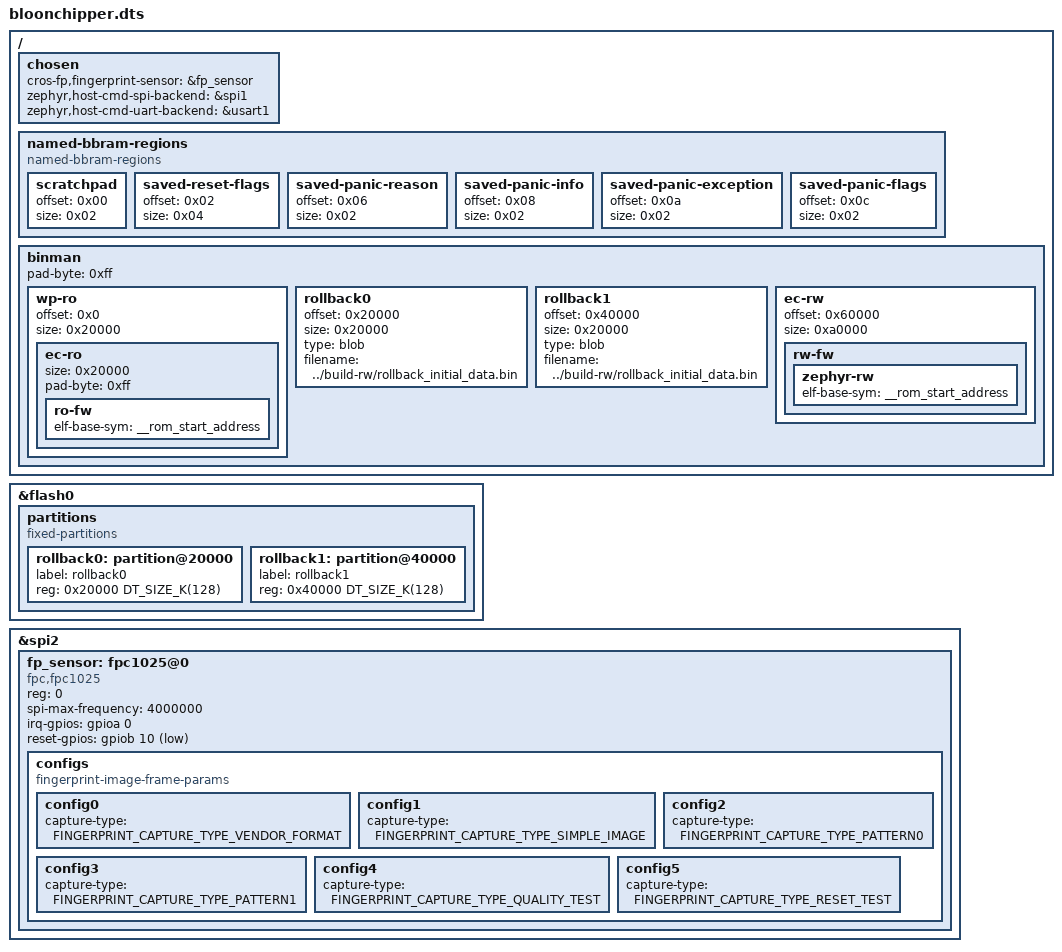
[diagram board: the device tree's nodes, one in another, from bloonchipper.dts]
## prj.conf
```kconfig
# Copyright 2023 The ChromiumOS Authors
# Use of this source code is governed by a BSD-style license that can be
# found in the LICENSE file.

# Force NUM_IRQ to 97, current upstream Zephyr computes that to a lower value.
CONFIG_NUM_IRQS=97

CONFIG_BOARD_BLOONCHIPPER=y

# The NULL pointer exception page size must be a power of two
# and have size greater or equal ARM_MPU_REGION_MIN_ALIGN_AND_SIZE
CONFIG_CORTEX_M_NULL_POINTER_EXCEPTION_PAGE_SIZE=0x80

# Peripherials
CONFIG_COUNTER=y
CONFIG_DMA=y

# Power Management
CONFIG_PM=y
CONFIG_PM_DEVICE=y

# Hwinfo (used by cros-system driver for STM32)
CONFIG_HWINFO=y

# STM32 flash driver options
CONFIG_FLASH_STM32_READOUT_PROTECTION=y
CONFIG_FLASH_STM32_WRITE_PROTECT=y
CONFIG_FLASH_STM32_BLOCK_REGISTERS=y

# STM32 entropy driver options
CONFIG_ENTROPY_STM32_THR_POOL_SIZE=32
CONFIG_ENTROPY_STM32_THR_THRESHOLD=16

# IWDG watchdog
CONFIG_IWDG_STM32_INITIAL_TIMEOUT=10000
CONFIG_PLATFORM_EC_WATCHDOG_PERIOD_MS=10000
CONFIG_PLATFORM_EC_WATCHDOG_WARNING_LEADING_TIME_MS=3000
CONFIG_PLATFORM_EC_WATCHDOG_HELPER=y

# Set HOOK_TICK INTERVAL in microseconds to reload watchdog
CONFIG_CROS_EC_HOOK_TICK_INTERVAL=500000

# CrOS drivers
CONFIG_CROS_FLASH_READOUT_PROTECTION=y
CONFIG_CROS_SYSTEM_STM32=y

# Priorities
CONFIG_PLATFORM_EC_FLASH_INIT_PRIORITY=60
CONFIG_CROS_SYSTEM_INIT_PRIORITY=71
CONFIG_PLATFORM_EC_SYSTEM_PRE_INIT_PRIORITY=72

# Host Commands
CONFIG_EC_HOST_CMD_INITIALIZE_AT_BOOT=n
CONFIG_EC_HOST_CMD_HANDLER_TX_BUFFER_SIZE=549
CONFIG_EC_HOST_CMD_HANDLER_RX_BUFFER_SIZE=544
CONFIG_EC_HOST_CMD_BACKEND_SPI=y
CONFIG_EC_HOST_CMD_BACKEND_UART=y
CONFIG_EC_HOST_CMD_BACKEND_UART_TIMEOUT=30
CONFIG_UART_ASYNC_API=y

# Increase IDLE stack for the IDLE timer
CONFIG_IDLE_STACK_SIZE=550

# Enable DMA for SPI, which is used for communication with a sensor
CONFIG_SPI_STM32_DMA=y

# Software SHA256 for rollback and RW signature verification
CONFIG_PLATFORM_EC_SHA256_SW=y
CONFIG_PLATFORM_EC_SHA256_UNROLLED=y

# b/443091184
CONFIG_PLATFORM_EC_DEBUG_ASSERT=n

# Current rollback version value for bloonchipper.
CONFIG_PLATFORM_EC_ROLLBACK_VERSION=0

# Disable dropped logs tracking as limited on flash space.
CONFIG_PLATFORM_EC_HOSTCMD_CONSOLE_DROPPED_LOGS=n

# TODO(b/578101696): Enable INIT_ARCH_HW_AT_BOOT on bloonchipper.
CONFIG_INIT_ARCH_HW_AT_BOOT=n
```

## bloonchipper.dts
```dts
/* Copyright 2023 The ChromiumOS Authors.
 * Use of this source code is governed by a BSD-style license that can be
 * found in the LICENSE file.
 */

#include "soc.dtsi"
#include "gpio.dtsi"
#include "rwsig.dtsi"

#include <cros/integrated_fwid.dtsi>
#include <cros/integrated_ro_frid.dtsi>

#define FPC1025_BASE_IMAGE_PROPS \
    width = <160>; \
    height = <160>; \
    bits-per-pixel = <8>; \
    image-data-offset-bytes = <400>; \
    v4l2-pixel-format = "V4L2_PIX_FMT_GREY";

#define FPC1025_RAW_IMAGE_PROPS \
    FPC1025_BASE_IMAGE_PROPS \
    /*
     * Sensor raw image size
     *
     * Value from fpc_bep_image_get_buffer_size(): (160*160)+660
     */ \
    frame-size = <26260>;

#define FPC1025_REAL_IMAGE_PROPS \
    FPC1025_BASE_IMAGE_PROPS \
    /* Sensor real image size: (160*160) */ \
    frame-size = <25600>;

/ {
	chosen {
		cros-fp,fingerprint-sensor = &fp_sensor;
		zephyr,host-cmd-spi-backend = &spi1;
		zephyr,host-cmd-uart-backend = &usart1;
	};

	named-bbram-regions {
		compatible = "named-bbram-regions";

		scratchpad {
			offset = <0x00>;
			size = <0x02>;
		};
		saved-reset-flags {
			offset = <0x02>;
			size = <0x04>;
		};
		saved-panic-reason {
			offset = <0x06>;
			size = <0x02>;
		};
		saved-panic-info {
			offset = <0x08>;
			size = <0x02>;
		};
		saved-panic-exception {
			offset = <0x0a>;
			size = <0x02>;
		};
		saved-panic-flags {
			offset = <0x0c>;
			size = <0x02>;
		};
	};

	binman {
		pad-byte = <0xff>;

		/* First 5 sectors (4 x 16KB, 1 x 64KB) used for RO */
		wp-ro {
			offset = <0x0>;
			size = <0x20000>;
			ec-ro {
				size = <0x20000>;
				pad-byte = <0xff>;
				ro-fw {
					/*
					 * Clang doesn't emit STT_SECTION symbols (also
					 * called 'section symbols'), so 'rom_start'
					 * symbol is not available. Fortunately, Zephyr
					 * linker scripts provide '__rom_start_address'
					 * symbol which points to the beginning of
					 * 'rom_start' section.
					 */
					elf-base-sym = "__rom_start_address";
				};
			};
		};

		/* Two sectors used for rollback (128KB each) */
		rollback0 {
			offset = <0x20000>;
			size = <0x20000>;
			type = "blob";
			filename = "../build-rw/rollback_initial_data.bin";
		};

		rollback1 {
			offset = <0x40000>;
			size = <0x20000>;
			type = "blob";
			filename = "../build-rw/rollback_initial_data.bin";
		};

		/* Remaining 5 sectors (128KB each) used for RW */
		ec-rw {
			offset = <0x60000>;
			size = <0xa0000>;
			rw-fw {
				/*
				 * Clang doesn't emit STT_SECTION symbols (also
				 * called 'section symbols'), so 'rom_start'
				 * symbol is not available. Fortunately, Zephyr
				 * linker scripts provide '__rom_start_address'
				 * symbol which points to the beginning of
				 * 'rom_start' section.
				 */
				zephyr-rw {
					elf-base-sym = "__rom_start_address";
				};
			};
		};
	};
};

&flash0 {
	partitions {
		compatible = "fixed-partitions";
		#address-cells = <1>;
		#size-cells = <1>;

		/* Sixth sector is used as first rollback sector. */
		rollback0: partition@20000 {
			label = "rollback0";
			reg = <0x20000 DT_SIZE_K(128)>;
		};

		/* Seventh sector is used as second rollback sector. */
		rollback1: partition@40000 {
			label = "rollback1";
			reg = <0x40000 DT_SIZE_K(128)>;
		};
	};
};

&spi2 {
	fp_sensor: fpc1025@0 {
		compatible = "fpc,fpc1025";
		reg = <0>;
		spi-max-frequency = <4000000>;

		configs {
			compatible = "fingerprint-image-frame-params";
			config0 {
				FPC1025_RAW_IMAGE_PROPS
				capture-type = "FINGERPRINT_CAPTURE_TYPE_VENDOR_FORMAT";
			};
			config1 {
				FPC1025_REAL_IMAGE_PROPS
				capture-type = "FINGERPRINT_CAPTURE_TYPE_SIMPLE_IMAGE";
			};
			config2 {
				FPC1025_REAL_IMAGE_PROPS
				capture-type = "FINGERPRINT_CAPTURE_TYPE_PATTERN0";
			};
			config3 {
				FPC1025_REAL_IMAGE_PROPS
				capture-type = "FINGERPRINT_CAPTURE_TYPE_PATTERN1";
			};
			config4 {
				FPC1025_RAW_IMAGE_PROPS
				capture-type = "FINGERPRINT_CAPTURE_TYPE_QUALITY_TEST";
			};
			config5 {
				FPC1025_REAL_IMAGE_PROPS
				capture-type = "FINGERPRINT_CAPTURE_TYPE_RESET_TEST";
			};
		};

		irq-gpios = <&gpioa 0 (GPIO_ACTIVE_HIGH | GPIO_PULL_DOWN)>;
		reset-gpios = <&gpiob 10 GPIO_ACTIVE_LOW>;
	};
};
```

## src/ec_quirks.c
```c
/* Copyright 2023 The ChromiumOS Authors
 * Use of this source code is governed by a BSD-style license that can be
 * found in the LICENSE file.
 */

#include "system.h"

#include <zephyr/device.h>
#include <zephyr/devicetree.h>
#include <zephyr/drivers/clock_control/stm32_clock_control.h>
#include <zephyr/drivers/reset.h>
#include <zephyr/drivers/timer/system_timer.h>
#include <zephyr/init.h>
#include <zephyr/kernel.h>

#include <cmsis_core.h>
#include <stm32f4xx_ll_tim.h>

#define RESET_PERIPHERAL(idx) \
	reset_line_toggle_dt(&(struct reset_dt_spec)RESET_DT_SPEC_GET(idx));

#define TIMER2_NODE DT_NODELABEL(timers2)

void chip_pre_system_jump(void)
{
	/* Reset timers and UARTs to the defaults. */
	DT_FOREACH_STATUS_OKAY(st_stm32_timers, RESET_PERIPHERAL);
	DT_FOREACH_STATUS_OKAY(st_stm32_uart, RESET_PERIPHERAL);

	/*
	 * Disable system clock (Cortex-M Systick it this case) because it's
	 * unused in EC.
	 */
	sys_clock_disable();

	/*
	 * Legacy EC only uses PRIMASK for interrupt masking and does not
	 * clear BASEPRI in its reset handler. Mask PRIMASK and clear
	 * BASEPRI before jumping so Legacy EC enters init.S with
	 * PRIMASK=1 and BASEPRI=0.
	 */
	__disable_irq();
	__set_BASEPRI(0);
	__DSB();
	__ISB();
}

/*
 * Old FPMCU RO (EC based) uses TIM2 to measure system uptime and schedule
 * tasks. Zephyr uses different counter for these purposes, so disable it.
 */
static int disable_tim2(void)
{
	struct stm32_pclken pclken = { .bus = DT_CLOCKS_CELL(TIMER2_NODE, bus),
				       .enr = DT_CLOCKS_CELL(TIMER2_NODE,
							     bits) };
	LL_TIM_DisableCounter((TIM_TypeDef *)(DT_REG_ADDR(TIMER2_NODE)));
	irq_disable(DT_IRQN(TIMER2_NODE));

	clock_control_off(DEVICE_DT_GET(STM32_CLOCK_CONTROL_NODE),
			  (clock_control_subsys_t)&pclken);

	return 0;
}
SYS_INIT(disable_tim2, POST_KERNEL, CONFIG_APPLICATION_INIT_PRIORITY);
```
